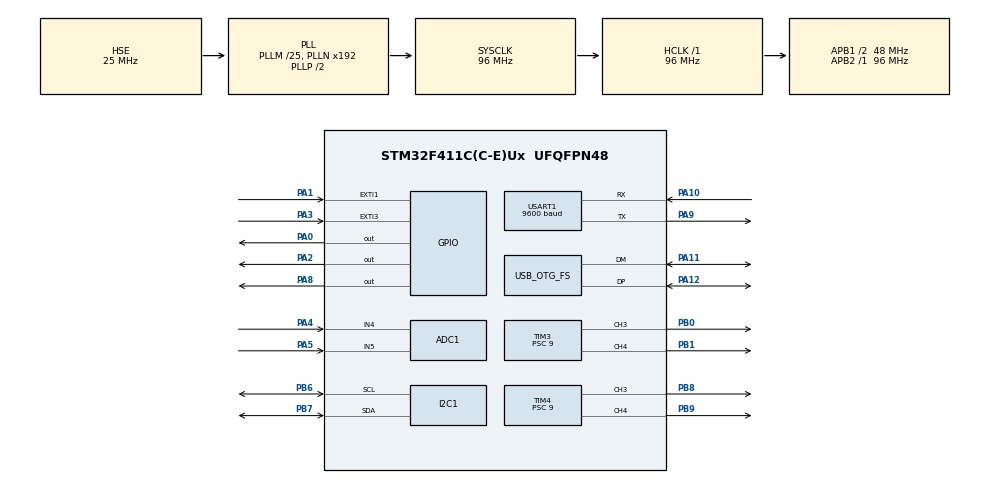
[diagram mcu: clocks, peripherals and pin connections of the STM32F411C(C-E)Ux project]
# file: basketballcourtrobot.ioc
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ADC1.Channel-0\#ChannelRegularConversion=ADC_CHANNEL_4
ADC1.NbrOfConversionFlag=1
ADC1.Rank-0\#ChannelRegularConversion=1
ADC1.SamplingTime-0\#ChannelRegularConversion=ADC_SAMPLETIME_3CYCLES
ADC1.master=1
Mcu.Family=STM32F4
Mcu.Name=STM32F411C(C-E)Ux
Mcu.Package=UFQFPN48
NVIC.OTG_FS_IRQn=true\:0\:0\:false\:false\:true\:false\:true\:true
NVIC.PriorityGroup=NVIC_PRIORITYGROUP_4
NVIC.USART1_IRQn=true\:0\:0\:false\:false\:true\:true\:true\:true
PA0-WKUP.Signal=GPIO_Output
PA1.Signal=GPXTI1
PA10.Mode=Asynchronous
PA10.Signal=USART1_RX
PA11.Mode=Device_Only
PA11.Signal=USB_OTG_FS_DM
PA12.Mode=Device_Only
PA12.Signal=USB_OTG_FS_DP
PA2.Signal=GPIO_Output
PA3.Signal=GPXTI3
PA4.Signal=ADCx_IN4
PA5.Signal=ADCx_IN5
PA8.Signal=GPIO_Output
PA9.Mode=Asynchronous
PA9.Signal=USART1_TX
PB0.Signal=S_TIM3_CH3
PB1.Signal=S_TIM3_CH4
PB6.Mode=I2C
PB6.Signal=I2C1_SCL
PB7.Mode=I2C
PB7.Signal=I2C1_SDA
PB8.Signal=S_TIM4_CH3
PB9.Signal=S_TIM4_CH4
PH0\ -\ OSC_IN.Mode=HSE-External-Oscillator
PH0\ -\ OSC_IN.Signal=RCC_OSC_IN
PH1\ -\ OSC_OUT.Mode=HSE-External-Oscillator
PH1\ -\ OSC_OUT.Signal=RCC_OSC_OUT
ProjectManager.HeapSize=0x200
ProjectManager.StackSize=0x400
ProjectManager.TargetToolchain=CMake
RCC.48MHZClocksFreq_Value=48000000
RCC.AHBFreq_Value=96000000
RCC.APB1CLKDivider=RCC_HCLK_DIV2
RCC.APB1Freq_Value=48000000
RCC.APB1TimFreq_Value=96000000
RCC.APB2Freq_Value=96000000
RCC.APB2TimFreq_Value=96000000
RCC.CortexFreq_Value=96000000
RCC.HCLKFreq_Value=96000000
RCC.HSE_VALUE=25000000
RCC.HSI_VALUE=16000000
RCC.LSE_VALUE=32768
RCC.PLLM=25
RCC.SYSCLKFreq_VALUE=96000000
RCC.SYSCLKSource=RCC_SYSCLKSOURCE_PLLCLK
RCC.VCOOutputFreq_Value=192000000
SH.ADCx_IN4.0=ADC1_IN4,IN4
SH.ADCx_IN5.0=ADC1_IN5,IN5
SH.S_TIM3_CH3.0=TIM3_CH3,PWM Generation3 CH3
SH.S_TIM3_CH4.0=TIM3_CH4,PWM Generation4 CH4
SH.S_TIM4_CH3.0=TIM4_CH3,PWM Generation3 CH3
SH.S_TIM4_CH4.0=TIM4_CH4,PWM Generation4 CH4
TIM3.Channel-PWM\ Generation3\ CH3=TIM_CHANNEL_3
TIM3.Channel-PWM\ Generation4\ CH4=TIM_CHANNEL_4
TIM3.Period=999
TIM3.Prescaler=9
TIM3.Pulse-PWM\ Generation3\ CH3=0
TIM3.Pulse-PWM\ Generation4\ CH4=0
TIM4.Channel-PWM\ Generation3\ CH3=TIM_CHANNEL_3
TIM4.Channel-PWM\ Generation4\ CH4=TIM_CHANNEL_4
TIM4.Period=999
TIM4.Prescaler=9
TIM4.Pulse-PWM\ Generation3\ CH3=0
TIM4.Pulse-PWM\ Generation4\ CH4=0
USART1.BaudRate=9600
USART1.VirtualMode=VM_ASYNC
USB_DEVICE.CLASS_NAME_FS=CDC
USB_DEVICE.VirtualMode=Cdc
USB_DEVICE.VirtualModeFS=Cdc_FS
USB_OTG_FS.VirtualMode=Device_Only
VP_USB_DEVICE_VS_USB_DEVICE_CDC_FS.Mode=CDC_FS
board=custom

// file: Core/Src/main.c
/* USER CODE BEGIN Header */
/**
  ******************************************************************************
  * @file           : main.c
  * @brief          : Main program body for Autonomous Basketball Court Cleaner
  ******************************************************************************
  * @attention
  *
  * Copyright (c) 2026 STMicroelectronics.
  * All rights reserved.
  *
  * This software is licensed under terms that can be found in the LICENSE file
  * in the root directory of this software component.
  * If no LICENSE file comes with this software, it is provided AS-IS.
  *
  ******************************************************************************
  */
/* USER CODE END Header */

#include "main.h"
#include "usb_device.h"

/* USER CODE BEGIN Includes */
#include <stdio.h>
#include <string.h>
#include "usbd_cdc_if.h"
#include "stm32f4xx_hal_tim.h"  // <--- Required for __HAL_TIM_GET_COUNTER, __HAL_TIM_SET_COMPARE, HAL_TIM_PWM_Start
#include "stm32f4xx_hal_uart.h" // <--- Required for HAL_UART_Receive_IT, UART_HandleTypeDef
/* USER CODE END Includes */

/* USER CODE BEGIN PD */
#define BATTERY_CUTOFF_VOLTAGE 9.6f  // 3.2V per cell minimum threshold
#define CURRENT_JAM_THRESHOLD  2800  // ADC threshold for ~15A stall spike on 775 motor
/* USER CODE END PD */

ADC_HandleTypeDef hadc1;
I2C_HandleTypeDef hi2c1;
TIM_HandleTypeDef htim3;
TIM_HandleTypeDef htim4;
UART_HandleTypeDef huart1;

/* USER CODE BEGIN PV */
uint8_t rx_byte;
volatile uint8_t pending_cmd = 0;       // Stores pending BT byte for the main loop
volatile uint8_t bt_cmd_flag = 0;       // Signals main loop that a command arrived
volatile uint32_t echo1_t1 = 0, echo1_t2 = 0;
volatile uint32_t echo2_t1 = 0, echo2_t2 = 0;
volatile float dist1_cm = 0.0f, dist2_cm = 0.0f;
volatile float battery_voltage = 12.0f;
/* USER CODE END PV */

void SystemClock_Config(void);
static void MX_GPIO_Init(void);
static void MX_ADC1_Init(void);
static void MX_I2C1_Init(void);
static void MX_TIM3_Init(void);
static void MX_TIM4_Init(void);
static void MX_USART1_UART_Init(void);

/* USER CODE BEGIN PFP */
void Motor_Set_Left(int16_t speed);
void Motor_Set_Right(int16_t speed);
void Motor_Set_Speed(int16_t left, int16_t right);
void USB_Print(const char *str);
void Process_Bluetooth_Command(uint8_t cmd);
float Read_ADC_Channel(uint32_t channel);
float Read_Battery_Voltage(void);
void Check_Roller_Stall(void);
void Enter_Stop_Mode(void);
void Trigger_Ultrasonic_Sensors(void);
void USB_Send_Initial_Boot_Log(void);
void Delay_us(uint16_t us);
float Read_Ultrasonic_Distance(uint16_t trig_pin, uint16_t echo_pin);
/* USER CODE END PFP */

/* Private user code --------------------------------------------------------- */

int main(void)
{

  /* MCU Configuration--------------------------------------------------------*/

  /* Reset of all peripherals, Initializes the Flash interface and the Systick. */
  HAL_Init();

  /* Configure the system clock */
  SystemClock_Config();

  /* Initialize all configured peripherals */
  MX_GPIO_Init();
  MX_ADC1_Init();
  MX_I2C1_Init();
  MX_TIM3_Init();
  MX_TIM4_Init();
  MX_USART1_UART_Init();
  MX_USB_DEVICE_Init();

  /* USER CODE BEGIN 2 */

  // 1. Start TIM3 counter base for microsecond delays
  HAL_TIM_Base_Start(&htim3);

  // 2. Enable Motor Driver Logic Gates via PA15
  HAL_GPIO_WritePin(GPIOA, GPIO_PIN_15, GPIO_PIN_SET);

  // 3. Start PWM Timer Channels for Left Motor Driver (TIM3 CH3 & CH4)
  HAL_TIM_PWM_Start(&htim3, TIM_CHANNEL_3); // PB0 - Left RPWM
  HAL_TIM_PWM_Start(&htim3, TIM_CHANNEL_4); // PB1 - Left LPWM

  // 4. Start PWM Timer Channels for Right Motor Driver (TIM4 CH3 & CH4)
  HAL_TIM_PWM_Start(&htim4, TIM_CHANNEL_3); // PB8 - Right RPWM
  HAL_TIM_PWM_Start(&htim4, TIM_CHANNEL_4); // PB9 - Right LPWM

  // 5. Arm Bluetooth Interrupt Listener
  HAL_UART_Receive_IT(&huart1, &rx_byte, 1);

  HAL_Delay(2000);
  USB_Send_Initial_Boot_Log();

  /* USER CODE END 2 */

  /* Infinite loop */
  /* USER CODE BEGIN WHILE */
  while (1)
  {
    // Check if a Bluetooth command was received in the background
    if (bt_cmd_flag) {
        uint8_t cmd_to_process = pending_cmd;
        bt_cmd_flag = 0; // Clear flag
        Process_Bluetooth_Command(cmd_to_process); // Safe to run USB_Print here
    }

    // 1. Read Battery Voltage
    battery_voltage = Read_Battery_Voltage();

    // 2. Crusher Stall Check
    Check_Roller_Stall();

    // 3. Read Ultrasonic Sensor Distances
    dist1_cm = Read_Ultrasonic_Distance(GPIO_PIN_0, GPIO_PIN_1);
    HAL_Delay(20);
    dist2_cm = Read_Ultrasonic_Distance(GPIO_PIN_2, GPIO_PIN_3);

    // 4. Print telemetry stream
    uint16_t b_volts = (uint16_t)battery_voltage;
    uint16_t b_cents = (uint16_t)((battery_voltage - b_volts) * 100.0f);

    uint16_t d1_w = (uint16_t)dist1_cm;
    uint16_t d1_f = (uint16_t)((dist1_cm - d1_w) * 10.0f);

    uint16_t d2_w = (uint16_t)dist2_cm;
    uint16_t d2_f = (uint16_t)((dist2_cm - d2_w) * 10.0f);

    char stream_buf[96];
    snprintf(stream_buf, sizeof(stream_buf),
             "Loop Running | Batt: %u.%02uV | D1: %u.%ucm | D2: %u.%ucm\r\n",
             b_volts, b_cents, d1_w, d1_f, d2_w, d2_f);

    USB_Print(stream_buf);
    HAL_GPIO_TogglePin(GPIOC, GPIO_PIN_13);
    HAL_Delay(300);
  }
  /* USER CODE END 3 */
}

void SystemClock_Config(void)
{
  RCC_OscInitTypeDef RCC_OscInitStruct = {0};
  RCC_ClkInitTypeDef RCC_ClkInitStruct = {0};

  /** Configure the main internal regulator output voltage
  */
  __HAL_RCC_PWR_CLK_ENABLE();
  __HAL_PWR_VOLTAGESCALING_CONFIG(PWR_REGULATOR_VOLTAGE_SCALE1);

  /** Initializes the RCC Oscillators according to the specified parameters
  * in the RCC_OscInitTypeDef structure.
  */
  RCC_OscInitStruct.OscillatorType = RCC_OSCILLATORTYPE_HSE;
  RCC_OscInitStruct.HSEState = RCC_HSE_ON;
  RCC_OscInitStruct.PLL.PLLState = RCC_PLL_ON;
  RCC_OscInitStruct.PLL.PLLSource = RCC_PLLSOURCE_HSE;
  RCC_OscInitStruct.PLL.PLLM = 25;
  RCC_OscInitStruct.PLL.PLLN = 192;
  RCC_OscInitStruct.PLL.PLLP = RCC_PLLP_DIV2;
  RCC_OscInitStruct.PLL.PLLQ = 4;
  if (HAL_RCC_OscConfig(&RCC_OscInitStruct) != HAL_OK)
  {
    Error_Handler();
  }

  /** Initializes the CPU, AHB and APB buses clocks
  */
  RCC_ClkInitStruct.ClockType = RCC_CLOCKTYPE_HCLK|RCC_CLOCKTYPE_SYSCLK
                              |RCC_CLOCKTYPE_PCLK1|RCC_CLOCKTYPE_PCLK2;
  RCC_ClkInitStruct.SYSCLKSource = RCC_SYSCLKSOURCE_PLLCLK;
  RCC_ClkInitStruct.AHBCLKDivider = RCC_SYSCLK_DIV1;
  RCC_ClkInitStruct.APB1CLKDivider = RCC_HCLK_DIV2;
  RCC_ClkInitStruct.APB2CLKDivider = RCC_HCLK_DIV1;

  if (HAL_RCC_ClockConfig(&RCC_ClkInitStruct, FLASH_LATENCY_3) != HAL_OK)
  {
    Error_Handler();
  }
}

static void MX_ADC1_Init(void)
{

  ADC_ChannelConfTypeDef sConfig = {0};

  /** Configure the global features of the ADC (Clock, Resolution, Data Alignment and number of conversion)
  */
  hadc1.Instance = ADC1;
  hadc1.Init.ClockPrescaler = ADC_CLOCK_SYNC_PCLK_DIV4;
  hadc1.Init.Resolution = ADC_RESOLUTION_12B;
  hadc1.Init.ScanConvMode = DISABLE;
  hadc1.Init.ContinuousConvMode = DISABLE;
  hadc1.Init.DiscontinuousConvMode = DISABLE;
  hadc1.Init.ExternalTrigConvEdge = ADC_EXTERNALTRIGCONVEDGE_NONE;
  hadc1.Init.ExternalTrigConv = ADC_SOFTWARE_START;
  hadc1.Init.DataAlign = ADC_DATAALIGN_RIGHT;
  hadc1.Init.NbrOfConversion = 1;
  hadc1.Init.DMAContinuousRequests = DISABLE;
  hadc1.Init.EOCSelection = ADC_EOC_SINGLE_CONV;
  if (HAL_ADC_Init(&hadc1) != HAL_OK)
  {
    Error_Handler();
  }

  /** Configure for the selected ADC regular channel its corresponding rank in the sequencer and its sample time.
  */
  sConfig.Channel = ADC_CHANNEL_4;
  sConfig.Rank = 1;
  sConfig.SamplingTime = ADC_SAMPLETIME_3CYCLES;
  if (HAL_ADC_ConfigChannel(&hadc1, &sConfig) != HAL_OK)
  {
    Error_Handler();
  }

}

static void MX_I2C1_Init(void)
{

  hi2c1.Instance = I2C1;
  hi2c1.Init.ClockSpeed = 100000;
  hi2c1.Init.DutyCycle = I2C_DUTYCYCLE_2;
  hi2c1.Init.OwnAddress1 = 0;
  hi2c1.Init.AddressingMode = I2C_ADDRESSINGMODE_7BIT;
  hi2c1.Init.DualAddressMode = I2C_DUALADDRESS_DISABLE;
  hi2c1.Init.OwnAddress2 = 0;
  hi2c1.Init.GeneralCallMode = I2C_GENERALCALL_DISABLE;
  hi2c1.Init.NoStretchMode = I2C_NOSTRETCH_DISABLE;
  if (HAL_I2C_Init(&hi2c1) != HAL_OK)
  {
    Error_Handler();
  }

}

static void MX_TIM3_Init(void)
{

  TIM_MasterConfigTypeDef sMasterConfig = {0};
  TIM_OC_InitTypeDef sConfigOC = {0};

  htim3.Instance = TIM3;
  htim3.Init.Prescaler = 9;
  htim3.Init.CounterMode = TIM_COUNTERMODE_UP;
  htim3.Init.Period = 999;
  htim3.Init.ClockDivision = TIM_CLOCKDIVISION_DIV1;
  htim3.Init.AutoReloadPreload = TIM_AUTORELOAD_PRELOAD_DISABLE;
  if (HAL_TIM_PWM_Init(&htim3) != HAL_OK)
  {
    Error_Handler();
  }
  sMasterConfig.MasterOutputTrigger = TIM_TRGO_RESET;
  sMasterConfig.MasterSlaveMode = TIM_MASTERSLAVEMODE_DISABLE;
  if (HAL_TIMEx_MasterConfigSynchronization(&htim3, &sMasterConfig) != HAL_OK)
  {
    Error_Handler();
  }
  sConfigOC.OCMode = TIM_OCMODE_PWM1;
  sConfigOC.Pulse = 0;
  sConfigOC.OCPolarity = TIM_OCPOLARITY_HIGH;
  sConfigOC.OCFastMode = TIM_OCFAST_DISABLE;
  if (HAL_TIM_PWM_ConfigChannel(&htim3, &sConfigOC, TIM_CHANNEL_3) != HAL_OK)
  {
    Error_Handler();
  }
  if (HAL_TIM_PWM_ConfigChannel(&htim3, &sConfigOC, TIM_CHANNEL_4) != HAL_OK)
  {
    Error_Handler();
  }
  HAL_TIM_MspPostInit(&htim3);

}

static void MX_TIM4_Init(void)
{

  TIM_MasterConfigTypeDef sMasterConfig = {0};
  TIM_OC_InitTypeDef sConfigOC = {0};

  htim4.Instance = TIM4;
  htim4.Init.Prescaler = 9;
  htim4.Init.CounterMode = TIM_COUNTERMODE_UP;
  htim4.Init.Period = 999;
  htim4.Init.ClockDivision = TIM_CLOCKDIVISION_DIV1;
  htim4.Init.AutoReloadPreload = TIM_AUTORELOAD_PRELOAD_DISABLE;
  if (HAL_TIM_PWM_Init(&htim4) != HAL_OK)
  {
    Error_Handler();
  }
  sMasterConfig.MasterOutputTrigger = TIM_TRGO_RESET;
  sMasterConfig.MasterSlaveMode = TIM_MASTERSLAVEMODE_DISABLE;
  if (HAL_TIMEx_MasterConfigSynchronization(&htim4, &sMasterConfig) != HAL_OK)
  {
    Error_Handler();
  }
  sConfigOC.OCMode = TIM_OCMODE_PWM1;
  sConfigOC.Pulse = 0;
  sConfigOC.OCPolarity = TIM_OCPOLARITY_HIGH;
  sConfigOC.OCFastMode = TIM_OCFAST_DISABLE;
  if (HAL_TIM_PWM_ConfigChannel(&htim4, &sConfigOC, TIM_CHANNEL_3) != HAL_OK)
  {
    Error_Handler();
  }
  if (HAL_TIM_PWM_ConfigChannel(&htim4, &sConfigOC, TIM_CHANNEL_4) != HAL_OK)
  {
    Error_Handler();
  }
  HAL_TIM_MspPostInit(&htim4);

}

static void MX_USART1_UART_Init(void)
{

  huart1.Instance = USART1;
  huart1.Init.BaudRate = 9600;
  huart1.Init.WordLength = UART_WORDLENGTH_8B;
  huart1.Init.StopBits = UART_STOPBITS_1;
  huart1.Init.Parity = UART_PARITY_NONE;
  huart1.Init.Mode = UART_MODE_TX_RX;
  huart1.Init.HwFlowCtl = UART_HWCONTROL_NONE;
  huart1.Init.OverSampling = UART_OVERSAMPLING_16;
  if (HAL_UART_Init(&huart1) != HAL_OK)
  {
    Error_Handler();
  }

}

static void MX_GPIO_Init(void)
{
  GPIO_InitTypeDef GPIO_InitStruct = {0};

  /* GPIO Ports Clock Enable */
  __HAL_RCC_GPIOH_CLK_ENABLE();
  __HAL_RCC_GPIOA_CLK_ENABLE();
  __HAL_RCC_GPIOB_CLK_ENABLE();
  __HAL_RCC_GPIOC_CLK_ENABLE(); // Onboard Blue LED Clock

  /* Configure Output Pin Levels */
  HAL_GPIO_WritePin(GPIOA, GPIO_PIN_0|GPIO_PIN_2|GPIO_PIN_8|GPIO_PIN_15, GPIO_PIN_RESET);
  HAL_GPIO_WritePin(GPIOC, GPIO_PIN_13, GPIO_PIN_SET); // Set PC13 High (LED OFF)

  /* Configure GPIO Pins: PA0 (Trig1), PA2 (Trig2), PA8 (Crusher Gate), PA15 (BTS Enable) */
  GPIO_InitStruct.Pin = GPIO_PIN_0|GPIO_PIN_2|GPIO_PIN_8|GPIO_PIN_15;
  GPIO_InitStruct.Mode = GPIO_MODE_OUTPUT_PP;
  GPIO_InitStruct.Pull = GPIO_NOPULL;
  GPIO_InitStruct.Speed = GPIO_SPEED_FREQ_LOW;
  HAL_GPIO_Init(GPIOA, &GPIO_InitStruct);

  /* Configure Onboard LED (PC13) */
  GPIO_InitStruct.Pin = GPIO_PIN_13;
  GPIO_InitStruct.Mode = GPIO_MODE_OUTPUT_PP;
  GPIO_InitStruct.Pull = GPIO_NOPULL;
  GPIO_InitStruct.Speed = GPIO_SPEED_FREQ_LOW;
  HAL_GPIO_Init(GPIOC, &GPIO_InitStruct);

  /* Configure Echo Inputs: PA1 (Echo1), PA3 (Echo2) */
  GPIO_InitStruct.Pin = GPIO_PIN_1|GPIO_PIN_3;
  GPIO_InitStruct.Mode = GPIO_MODE_IT_RISING_FALLING;
  GPIO_InitStruct.Pull = GPIO_NOPULL;
  HAL_GPIO_Init(GPIOA, &GPIO_InitStruct);
}

// Left Motor Driver Control (TIM3 CH3 / CH4 on PB0 / PB1)
void Motor_Set_Left(int16_t speed) {
    if (speed > 0) {
        __HAL_TIM_SET_COMPARE(&htim3, TIM_CHANNEL_3, speed);
        __HAL_TIM_SET_COMPARE(&htim3, TIM_CHANNEL_4, 0);
    } else if (speed < 0) {
        __HAL_TIM_SET_COMPARE(&htim3, TIM_CHANNEL_3, 0);
        __HAL_TIM_SET_COMPARE(&htim3, TIM_CHANNEL_4, -speed);
    } else {
        __HAL_TIM_SET_COMPARE(&htim3, TIM_CHANNEL_3, 0);
        __HAL_TIM_SET_COMPARE(&htim3, TIM_CHANNEL_4, 0);
    }
}

// Right Motor Driver Control (TIM4 CH3 / CH4 on PB8 / PB9)
void Motor_Set_Right(int16_t speed) {
    if (speed > 0) {
        __HAL_TIM_SET_COMPARE(&htim4, TIM_CHANNEL_3, speed);
        __HAL_TIM_SET_COMPARE(&htim4, TIM_CHANNEL_4, 0);
    } else if (speed < 0) {
        __HAL_TIM_SET_COMPARE(&htim4, TIM_CHANNEL_3, 0);
        __HAL_TIM_SET_COMPARE(&htim4, TIM_CHANNEL_4, -speed);
    } else {
        __HAL_TIM_SET_COMPARE(&htim4, TIM_CHANNEL_3, 0);
        __HAL_TIM_SET_COMPARE(&htim4, TIM_CHANNEL_4, 0);
    }
}

void Motor_Set_Speed(int16_t left, int16_t right) {
    Motor_Set_Left(left);
    Motor_Set_Right(right);
}

/* USER CODE BEGIN 4 */

// 1. FAST & SAFE ISR: Non-blocking, no USB printing here!
void HAL_UART_RxCpltCallback(UART_HandleTypeDef *huart) {
    if (huart->Instance == USART1) {
        // Filter out carriage returns, line feeds, and spaces immediately
        if (rx_byte != '\r' && rx_byte != '\n' && rx_byte != ' ' && rx_byte != 0x00) {
            pending_cmd = rx_byte;
            bt_cmd_flag = 1; // Hand off to main loop
        }

        // Re-arm interrupt for next byte
        HAL_UART_Receive_IT(&huart1, &rx_byte, 1);
    }
}

// 2. Executed safely in the main thread context
void Process_Bluetooth_Command(uint8_t cmd) {
    char bt_log[64];
    snprintf(bt_log, sizeof(bt_log), "\r\n>>> [BT CMD RECEIVED]: '%c' (0x%02X)\r\n", cmd, cmd);
    USB_Print(bt_log);

    switch (cmd) {
        case 'F': case 'f':
            Motor_Set_Speed(700, 700);
            USB_Print("    └─ Action: Moving FORWARD\r\n");
            break;

        case 'B': case 'b':
            Motor_Set_Speed(-700, -700);
            USB_Print("    └─ Action: Moving REVERSE\r\n");
            break;

        case 'L': case 'l':
            Motor_Set_Speed(-500, 500);
            USB_Print("    └─ Action: Spinning LEFT\r\n");
            break;

        case 'R': case 'r':
            Motor_Set_Speed(500, -500);
            USB_Print("    └─ Action: Spinning RIGHT\r\n");
            break;

        case 'S': case 's':
            Motor_Set_Speed(0, 0);
            USB_Print("    └─ Action: STOP All Motors\r\n");
            break;

        case 'C': case 'c':
            HAL_GPIO_TogglePin(GPIOA, GPIO_PIN_8);
            USB_Print("    └─ Action: Toggled Crusher Motor (PA8)\r\n");
            break;

        case 'Z': case 'z':
            USB_Print("    └─ Action: Entering Low-Power STOP Mode\r\n");
            Enter_Stop_Mode();
            break;

        default:
            break;
    }
}

// 3. Non-blocking USB Print helper
void USB_Print(const char *str) {
    uint8_t result;
    uint16_t retry = 1000;

    // Poll without calling HAL_Delay
    do {
        result = CDC_Transmit_FS((uint8_t *)str, strlen(str));
        if (result == USBD_OK) break;
    } while (--retry > 0);
}

// Single-Channel ADC Polling Utility
float Read_ADC_Channel(uint32_t channel) {
    ADC_ChannelConfTypeDef sConfig = {0};
    sConfig.Channel = channel;
    sConfig.Rank = 1;
    sConfig.SamplingTime = ADC_SAMPLETIME_144CYCLES;
    HAL_ADC_ConfigChannel(&hadc1, &sConfig);

    HAL_ADC_Start(&hadc1);
    if (HAL_ADC_PollForConversion(&hadc1, 10) == HAL_OK) {
        uint32_t raw = HAL_ADC_GetValue(&hadc1);
        HAL_ADC_Stop(&hadc1);
        return (float)raw;
    }
    HAL_ADC_Stop(&hadc1);
    return 0.0f;
}

// Battery Voltage Calculation via PA5 Resistor Divider
float Read_Battery_Voltage(void) {
    float raw_adc = Read_ADC_Channel(ADC_CHANNEL_5);
    float pin_v = (raw_adc * 3.3f) / 4095.0f;
    return pin_v * 4.251f;
}

// Automatic Crusher Jam Detection Strategy
void Check_Roller_Stall(void) {
    float current_raw = Read_ADC_Channel(ADC_CHANNEL_4);
    if (current_raw > CURRENT_JAM_THRESHOLD) {
        HAL_GPIO_WritePin(GPIOA, GPIO_PIN_8, GPIO_PIN_RESET);
        Motor_Set_Speed(-600, -600);
        HAL_Delay(800);
        Motor_Set_Speed(0, 0);
    }
}

// Low-Power STOP Mode Execution
void Enter_Stop_Mode(void) {
    Motor_Set_Speed(0, 0);
    HAL_GPIO_WritePin(GPIOA, GPIO_PIN_15, GPIO_PIN_RESET);
    HAL_GPIO_WritePin(GPIOA, GPIO_PIN_8, GPIO_PIN_RESET);

    HAL_SuspendTick();
    HAL_PWR_EnterSTOPMode(PWR_LOWPOWERREGULATOR_ON, PWR_STOPENTRY_WFI);

    // --- MCU Sleeps Here Until Woken By Interrupt ---

    SystemClock_Config();
    HAL_ResumeTick();
    HAL_GPIO_WritePin(GPIOA, GPIO_PIN_15, GPIO_PIN_SET);
}

// Ultrasonic Echo Interrupt Callback
void HAL_GPIO_EXTI_Callback(uint16_t GPIO_Pin) {
    if (GPIO_Pin == GPIO_PIN_1) { // Echo Sensor 1 (PA1)
        if (HAL_GPIO_ReadPin(GPIOA, GPIO_PIN_1) == GPIO_PIN_SET) {
            echo1_t1 = __HAL_TIM_GET_COUNTER(&htim3);
        } else {
            echo1_t2 = __HAL_TIM_GET_COUNTER(&htim3);
            uint32_t duration = (echo1_t2 >= echo1_t1) ? (echo1_t2 - echo1_t1) : ((65535 - echo1_t1) + echo1_t2);
            dist1_cm = (float)duration * 0.01715f;
        }
    }
    if (GPIO_Pin == GPIO_PIN_3) { // Echo Sensor 2 (PA3)
        if (HAL_GPIO_ReadPin(GPIOA, GPIO_PIN_3) == GPIO_PIN_SET) {
            echo2_t1 = __HAL_TIM_GET_COUNTER(&htim3);
        } else {
            echo2_t2 = __HAL_TIM_GET_COUNTER(&htim3);
            uint32_t duration = (echo2_t2 >= echo2_t1) ? (echo2_t2 - echo2_t1) : ((65535 - echo2_t2) + echo2_t2);
            dist2_cm = (float)duration * 0.01715f;
        }
    }
}

// Precise microsecond delay using running TIM3 counter
void Delay_us(uint16_t us) {
    uint16_t start = __HAL_TIM_GET_COUNTER(&htim3);
    while ((uint16_t)(__HAL_TIM_GET_COUNTER(&htim3) - start) < us);
}

void Trigger_Ultrasonic_Sensors(void) {
    // Pulse PA0 (Trigger 1)
    HAL_GPIO_WritePin(GPIOA, GPIO_PIN_0, GPIO_PIN_SET);
    Delay_us(12); // 12 us pulse guarantees > 10us threshold
    HAL_GPIO_WritePin(GPIOA, GPIO_PIN_0, GPIO_PIN_RESET);

    Delay_us(10);

    // Pulse PA2 (Trigger 2)
    HAL_GPIO_WritePin(GPIOA, GPIO_PIN_2, GPIO_PIN_SET);
    Delay_us(12);
    HAL_GPIO_WritePin(GPIOA, GPIO_PIN_2, GPIO_PIN_RESET);
}

// Diagnostics Dump Executed On Boot
void USB_Send_Initial_Boot_Log(void) {
    char log_buf[128];

    USB_Print("\r\n================================================\r\n");
    USB_Print("  AUTONOMOUS BASKETBALL COURT CLEANER - BOOT LOG \r\n");
    USB_Print("================================================\r\n");

    snprintf(log_buf, sizeof(log_buf), "SYSCLK Target Speed : %lu MHz\r\n", HAL_RCC_GetSysClockFreq() / 1000000UL);
    USB_Print(log_buf);

    snprintf(log_buf, sizeof(log_buf), "HCLK Speed          : %lu MHz\r\n", HAL_RCC_GetHCLKFreq() / 1000000UL);
    USB_Print(log_buf);

    snprintf(log_buf, sizeof(log_buf), "PCLK1 Bus Speed     : %lu MHz\r\n", HAL_RCC_GetPCLK1Freq() / 1000000UL);
    USB_Print(log_buf);

    snprintf(log_buf, sizeof(log_buf), "PCLK2 Bus Speed     : %lu MHz\r\n", HAL_RCC_GetPCLK2Freq() / 1000000UL);
    USB_Print(log_buf);

    USB_Print("------------------------------------------------\r\n");
    USB_Print("Peripheral Status Setup:\r\n");
    USB_Print(" [OK] TIM3 CH3/CH4 PWM Motor Driver (Left)\r\n");
    USB_Print(" [OK] TIM4 CH3/CH4 PWM Motor Driver (Right)\r\n");
    USB_Print(" [OK] USART1 Bluetooth Listener (9600 Baud)\r\n");
    USB_Print(" [OK] EXTI Line 1 / Line 3 Ultrasonic Echo Subsystem\r\n");

    float batt = Read_Battery_Voltage();
    snprintf(log_buf, sizeof(log_buf), " [OK] ADC Channel 5 LiPo Battery Rail: %.2f V\r\n", batt);
    USB_Print(log_buf);

    USB_Print("================================================\r\n");
    USB_Print("System operational. Entering autonomous loop...\r\n\r\n");
}

// Ultrasonic Polling Utility
float Read_Ultrasonic_Distance(uint16_t trig_pin, uint16_t echo_pin) {
    uint32_t t1 = 0, t2 = 0;
    uint32_t timeout = 30000; // ~30ms max timeout

    // Send 12us HIGH Trigger Pulse
    HAL_GPIO_WritePin(GPIOA, trig_pin, GPIO_PIN_SET);
    Delay_us(12);
    HAL_GPIO_WritePin(GPIOA, trig_pin, GPIO_PIN_RESET);

    // Wait for Echo Pin to go HIGH
    while (HAL_GPIO_ReadPin(GPIOA, echo_pin) == GPIO_PIN_RESET) {
        if (--timeout == 0) return 0.0f;
    }
    t1 = __HAL_TIM_GET_COUNTER(&htim3);

    // Wait for Echo Pin to go LOW
    timeout = 30000;
    while (HAL_GPIO_ReadPin(GPIOA, echo_pin) == GPIO_PIN_SET) {
        if (--timeout == 0) return 0.0f;
    }
    t2 = __HAL_TIM_GET_COUNTER(&htim3);

    // Compute duration considering 16-bit timer overflow
    uint32_t duration = (t2 >= t1) ? (t2 - t1) : ((65535 - t1) + t2);

    return (float)duration * 0.01715f;
}

/* USER CODE END 4 */

void Error_Handler(void)
{
  __disable_irq();
  while (1)
  {
  }
}
